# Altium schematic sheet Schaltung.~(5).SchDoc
size A4

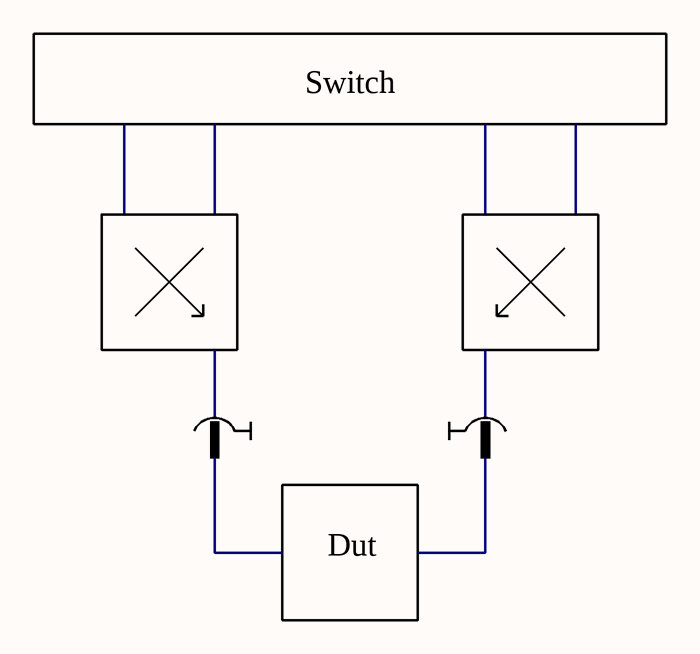
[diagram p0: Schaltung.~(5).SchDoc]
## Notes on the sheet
- Switch
- Dut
